One B-rep face of a CAD part: STEP entity #827.
In plain terms, the planar face has unit normal (0, 0, -1).
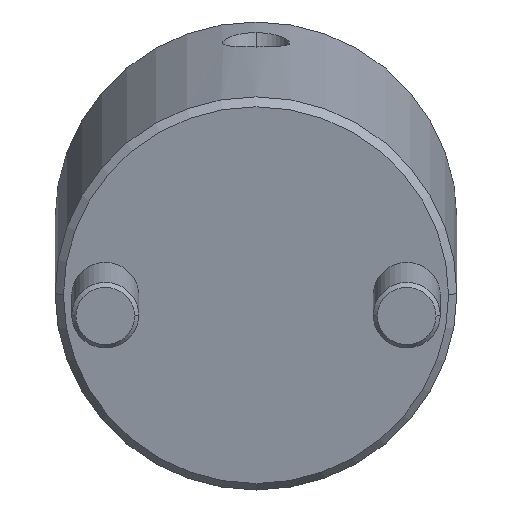
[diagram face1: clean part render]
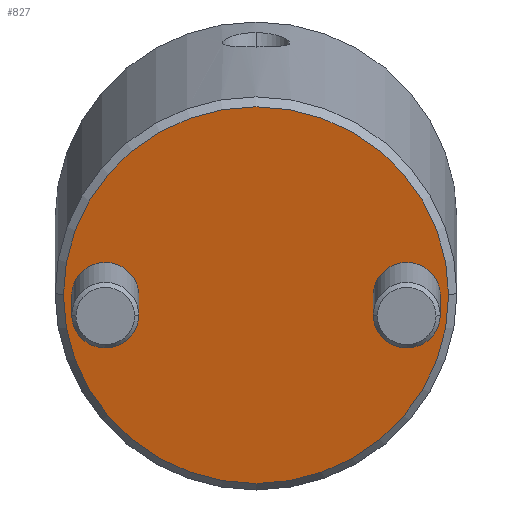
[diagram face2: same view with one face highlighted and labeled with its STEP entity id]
Its self-contained STEP definition (entity closure, numbers rounded to 3 decimals):
#428=CARTESIAN_POINT('',(0.,0.,0.));
#429=DIRECTION('',(0.,0.,-1.));
#430=DIRECTION('',(0.,-1.,0.));
#431=AXIS2_PLACEMENT_3D('',#428,#429,#430);
#433=CARTESIAN_POINT('',(0.,0.,
0.));
#434=DIRECTION('',(0.,0.,-1.));
#435=DIRECTION('',(0.,1.,0.));
#436=AXIS2_PLACEMENT_3D('',#433,#434,#435);
#438=CARTESIAN_POINT('',(0.,-18.,0.));
#439=DIRECTION('',(0.,0.,-1.));
#440=DIRECTION('',(0.,-1.,0.));
#441=AXIS2_PLACEMENT_3D('',#438,#439,#440);
#443=CARTESIAN_POINT('',(0.,-18.,0.));
#444=DIRECTION('',(0.,0.,-1.));
#445=DIRECTION('',(0.,1.,0.));
#446=AXIS2_PLACEMENT_3D('',#443,#444,#445);
#448=CARTESIAN_POINT('',(0.,18.,0.));
#449=DIRECTION('',(0.,0.,-1.));
#450=DIRECTION('',(0.,-1.,0.));
#451=AXIS2_PLACEMENT_3D('',#448,#449,#450);
#453=CARTESIAN_POINT('',(0.,18.,0.));
#454=DIRECTION('',(0.,0.,-1.));
#455=DIRECTION('',(0.,1.,0.));
#456=AXIS2_PLACEMENT_3D('',#453,#454,#455);
#754=CARTESIAN_POINT('',(0.,-23.,0.));
#755=CARTESIAN_POINT('',(0.,23.,0.));
#756=VERTEX_POINT('',#754);
#757=VERTEX_POINT('',#755);
#780=CARTESIAN_POINT('',(0.,-22.,0.));
#781=CARTESIAN_POINT('',(0.,-14.,0.));
#782=VERTEX_POINT('',#780);
#783=VERTEX_POINT('',#781);
#784=CARTESIAN_POINT('',(0.,14.,0.));
#785=CARTESIAN_POINT('',(0.,22.,0.));
#786=VERTEX_POINT('',#784);
#787=VERTEX_POINT('',#785);
#804=CARTESIAN_POINT('',(0.,0.,0.));
#805=DIRECTION('',(0.,0.,1.));
#806=DIRECTION('',(0.,1.,0.));
#807=AXIS2_PLACEMENT_3D('',#804,#805,#806);
#808=PLANE('',#807);
#810=ORIENTED_EDGE('',*,*,#809,.F.);
#812=ORIENTED_EDGE('',*,*,#811,.F.);
#813=EDGE_LOOP('',(#810,#812));
#814=FACE_OUTER_BOUND('',#813,.F.);
#816=ORIENTED_EDGE('',*,*,#815,.T.);
#818=ORIENTED_EDGE('',*,*,#817,.T.);
#819=EDGE_LOOP('',(#816,#818));
#820=FACE_BOUND('',#819,.F.);
#822=ORIENTED_EDGE('',*,*,#821,.T.);
#824=ORIENTED_EDGE('',*,*,#823,.T.);
#825=EDGE_LOOP('',(#822,#824));
#826=FACE_BOUND('',#825,.F.);
#827=ADVANCED_FACE('',(#814,#820,#826),#808,.F.);
#432=CIRCLE('',#431,23.);
#437=CIRCLE('',#436,23.);
#442=CIRCLE('',#441,4.);
#447=CIRCLE('',#446,4.);
#452=CIRCLE('',#451,4.);
#457=CIRCLE('',#456,4.);
#809=EDGE_CURVE('',#756,#757,#432,.T.);
#811=EDGE_CURVE('',#757,#756,#437,.T.);
#815=EDGE_CURVE('',#782,#783,#442,.T.);
#817=EDGE_CURVE('',#783,#782,#447,.T.);
#821=EDGE_CURVE('',#786,#787,#452,.T.);
#823=EDGE_CURVE('',#787,#786,#457,.T.);
